# Generated by FakeRAM 2.0 (routing-friendly)
VERSION 5.7 ;
BUSBITCHARS "[]" ;
PROPERTYDEFINITIONS
  MACRO width INTEGER ;
  MACRO depth INTEGER ;
  MACRO banks INTEGER ;
END PROPERTYDEFINITIONS
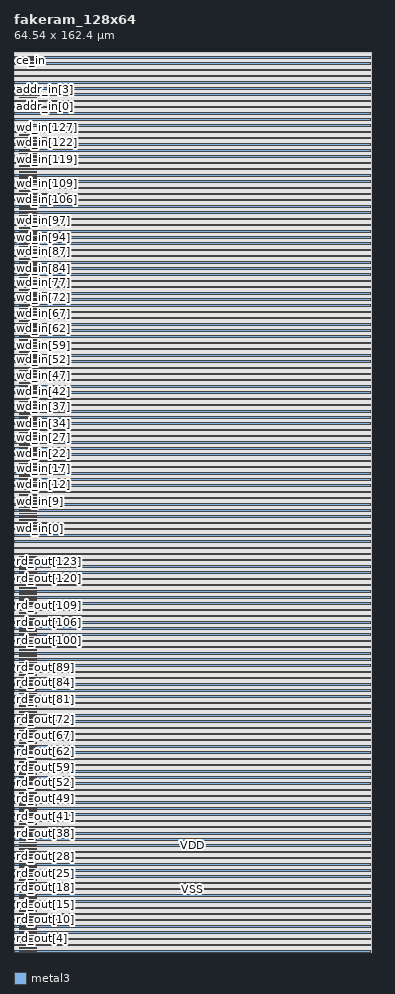
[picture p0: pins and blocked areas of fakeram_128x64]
MACRO fakeram_128x64
  PROPERTY width 128 ;
  PROPERTY depth 64 ;
  PROPERTY banks 1 ;
  FOREIGN fakeram_128x64 0 0 ;
  SYMMETRY X Y R90 ;
  SIZE 64.540 BY 162.400 ;
  CLASS BLOCK ;
  PIN rd_out[0]
    DIRECTION OUTPUT ;
    USE SIGNAL ;
    PORT
      LAYER metal3 ;
      RECT 1.000 0.140 3.000 0.210 ;
    END
    PORT
      LAYER metal3 ;
      RECT 1.000 0.105 4.000 0.245 ;
    END
  END rd_out[0]
  PIN rd_out[1]
    DIRECTION OUTPUT ;
    USE SIGNAL ;
    PORT
      LAYER metal3 ;
      RECT 1.000 0.700 3.000 0.770 ;
    END
    PORT
      LAYER metal3 ;
      RECT 1.000 0.665 4.000 0.805 ;
    END
  END rd_out[1]
  PIN rd_out[2]
    DIRECTION OUTPUT ;
    USE SIGNAL ;
    PORT
      LAYER metal3 ;
      RECT 1.000 1.260 3.000 1.330 ;
    END
    PORT
      LAYER metal3 ;
      RECT 1.000 1.225 4.000 1.365 ;
    END
  END rd_out[2]
  PIN rd_out[3]
    DIRECTION OUTPUT ;
    USE SIGNAL ;
    PORT
      LAYER metal3 ;
      RECT 1.000 1.820 3.000 1.890 ;
    END
    PORT
      LAYER metal3 ;
      RECT 1.000 1.785 4.000 1.925 ;
    END
  END rd_out[3]
  PIN rd_out[4]
    DIRECTION OUTPUT ;
    USE SIGNAL ;
    PORT
      LAYER metal3 ;
      RECT 1.000 2.380 3.000 2.450 ;
    END
    PORT
      LAYER metal3 ;
      RECT 1.000 2.345 4.000 2.485 ;
    END
  END rd_out[4]
  PIN rd_out[5]
    DIRECTION OUTPUT ;
    USE SIGNAL ;
    PORT
      LAYER metal3 ;
      RECT 1.000 2.940 3.000 3.010 ;
    END
    PORT
      LAYER metal3 ;
      RECT 1.000 2.905 4.000 3.045 ;
    END
  END rd_out[5]
  PIN rd_out[6]
    DIRECTION OUTPUT ;
    USE SIGNAL ;
    PORT
      LAYER metal3 ;
      RECT 1.000 3.500 3.000 3.570 ;
    END
    PORT
      LAYER metal3 ;
      RECT 1.000 3.465 4.000 3.605 ;
    END
  END rd_out[6]
  PIN rd_out[7]
    DIRECTION OUTPUT ;
    USE SIGNAL ;
    PORT
      LAYER metal3 ;
      RECT 1.000 4.060 3.000 4.130 ;
    END
    PORT
      LAYER metal3 ;
      RECT 1.000 4.025 4.000 4.165 ;
    END
  END rd_out[7]
  PIN rd_out[8]
    DIRECTION OUTPUT ;
    USE SIGNAL ;
    PORT
      LAYER metal3 ;
      RECT 1.000 4.620 3.000 4.690 ;
    END
    PORT
      LAYER metal3 ;
      RECT 1.000 4.585 4.000 4.725 ;
    END
  END rd_out[8]
  PIN rd_out[9]
    DIRECTION OUTPUT ;
    USE SIGNAL ;
    PORT
      LAYER metal3 ;
      RECT 1.000 5.180 3.000 5.250 ;
    END
    PORT
      LAYER metal3 ;
      RECT 1.000 5.145 4.000 5.285 ;
    END
  END rd_out[9]
  PIN rd_out[10]
    DIRECTION OUTPUT ;
    USE SIGNAL ;
    PORT
      LAYER metal3 ;
      RECT 1.000 5.740 3.000 5.810 ;
    END
    PORT
      LAYER metal3 ;
      RECT 1.000 5.705 4.000 5.845 ;
    END
  END rd_out[10]
  PIN rd_out[11]
    DIRECTION OUTPUT ;
    USE SIGNAL ;
    PORT
      LAYER metal3 ;
      RECT 1.000 6.300 3.000 6.370 ;
    END
    PORT
      LAYER metal3 ;
      RECT 1.000 6.265 4.000 6.405 ;
    END
  END rd_out[11]
  PIN rd_out[12]
    DIRECTION OUTPUT ;
    USE SIGNAL ;
    PORT
      LAYER metal3 ;
      RECT 1.000 6.860 3.000 6.930 ;
    END
    PORT
      LAYER metal3 ;
      RECT 1.000 6.825 4.000 6.965 ;
    END
  END rd_out[12]
  PIN rd_out[13]
    DIRECTION OUTPUT ;
    USE SIGNAL ;
    PORT
      LAYER metal3 ;
      RECT 1.000 7.420 3.000 7.490 ;
    END
    PORT
      LAYER metal3 ;
      RECT 1.000 7.385 4.000 7.525 ;
    END
  END rd_out[13]
  PIN rd_out[14]
    DIRECTION OUTPUT ;
    USE SIGNAL ;
    PORT
      LAYER metal3 ;
      RECT 1.000 7.980 3.000 8.050 ;
    END
    PORT
      LAYER metal3 ;
      RECT 1.000 7.945 4.000 8.085 ;
    END
  END rd_out[14]
  PIN rd_out[15]
    DIRECTION OUTPUT ;
    USE SIGNAL ;
    PORT
      LAYER metal3 ;
      RECT 1.000 8.540 3.000 8.610 ;
    END
    PORT
      LAYER metal3 ;
      RECT 1.000 8.505 4.000 8.645 ;
    END
  END rd_out[15]
  PIN rd_out[16]
    DIRECTION OUTPUT ;
    USE SIGNAL ;
    PORT
      LAYER metal3 ;
      RECT 1.000 9.100 3.000 9.170 ;
    END
    PORT
      LAYER metal3 ;
      RECT 1.000 9.065 4.000 9.205 ;
    END
  END rd_out[16]
  PIN rd_out[17]
    DIRECTION OUTPUT ;
    USE SIGNAL ;
    PORT
      LAYER metal3 ;
      RECT 1.000 9.660 3.000 9.730 ;
    END
    PORT
      LAYER metal3 ;
      RECT 1.000 9.625 4.000 9.765 ;
    END
  END rd_out[17]
  PIN rd_out[18]
    DIRECTION OUTPUT ;
    USE SIGNAL ;
    PORT
      LAYER metal3 ;
      RECT 1.000 10.220 3.000 10.290 ;
    END
    PORT
      LAYER metal3 ;
      RECT 1.000 10.185 4.000 10.325 ;
    END
  END rd_out[18]
  PIN rd_out[19]
    DIRECTION OUTPUT ;
    USE SIGNAL ;
    PORT
      LAYER metal3 ;
      RECT 1.000 10.780 3.000 10.850 ;
    END
    PORT
      LAYER metal3 ;
      RECT 1.000 10.745 4.000 10.885 ;
    END
  END rd_out[19]
  PIN rd_out[20]
    DIRECTION OUTPUT ;
    USE SIGNAL ;
    PORT
      LAYER metal3 ;
      RECT 1.000 11.340 3.000 11.410 ;
    END
    PORT
      LAYER metal3 ;
      RECT 1.000 11.305 4.000 11.445 ;
    END
  END rd_out[20]
  PIN rd_out[21]
    DIRECTION OUTPUT ;
    USE SIGNAL ;
    PORT
      LAYER metal3 ;
      RECT 1.000 11.900 3.000 11.970 ;
    END
    PORT
      LAYER metal3 ;
      RECT 1.000 11.865 4.000 12.005 ;
    END
  END rd_out[21]
  PIN rd_out[22]
    DIRECTION OUTPUT ;
    USE SIGNAL ;
    PORT
      LAYER metal3 ;
      RECT 1.000 12.460 3.000 12.530 ;
    END
    PORT
      LAYER metal3 ;
      RECT 1.000 12.425 4.000 12.565 ;
    END
  END rd_out[22]
  PIN rd_out[23]
    DIRECTION OUTPUT ;
    USE SIGNAL ;
    PORT
      LAYER metal3 ;
      RECT 1.000 13.020 3.000 13.090 ;
    END
    PORT
      LAYER metal3 ;
      RECT 1.000 12.985 4.000 13.125 ;
    END
  END rd_out[23]
  PIN rd_out[24]
    DIRECTION OUTPUT ;
    USE SIGNAL ;
    PORT
      LAYER metal3 ;
      RECT 1.000 13.580 3.000 13.650 ;
    END
    PORT
      LAYER metal3 ;
      RECT 1.000 13.545 4.000 13.685 ;
    END
  END rd_out[24]
  PIN rd_out[25]
    DIRECTION OUTPUT ;
    USE SIGNAL ;
    PORT
      LAYER metal3 ;
      RECT 1.000 14.140 3.000 14.210 ;
    END
    PORT
      LAYER metal3 ;
      RECT 1.000 14.105 4.000 14.245 ;
    END
  END rd_out[25]
  PIN rd_out[26]
    DIRECTION OUTPUT ;
    USE SIGNAL ;
    PORT
      LAYER metal3 ;
      RECT 1.000 14.700 3.000 14.770 ;
    END
    PORT
      LAYER metal3 ;
      RECT 1.000 14.665 4.000 14.805 ;
    END
  END rd_out[26]
  PIN rd_out[27]
    DIRECTION OUTPUT ;
    USE SIGNAL ;
    PORT
      LAYER metal3 ;
      RECT 1.000 15.260 3.000 15.330 ;
    END
    PORT
      LAYER metal3 ;
      RECT 1.000 15.225 4.000 15.365 ;
    END
  END rd_out[27]
  PIN rd_out[28]
    DIRECTION OUTPUT ;
    USE SIGNAL ;
    PORT
      LAYER metal3 ;
      RECT 1.000 15.820 3.000 15.890 ;
    END
    PORT
      LAYER metal3 ;
      RECT 1.000 15.785 4.000 15.925 ;
    END
  END rd_out[28]
  PIN rd_out[29]
    DIRECTION OUTPUT ;
    USE SIGNAL ;
    PORT
      LAYER metal3 ;
      RECT 1.000 16.380 3.000 16.450 ;
    END
    PORT
      LAYER metal3 ;
      RECT 1.000 16.345 4.000 16.485 ;
    END
  END rd_out[29]
  PIN rd_out[30]
    DIRECTION OUTPUT ;
    USE SIGNAL ;
    PORT
      LAYER metal3 ;
      RECT 1.000 16.940 3.000 17.010 ;
    END
    PORT
      LAYER metal3 ;
      RECT 1.000 16.905 4.000 17.045 ;
    END
  END rd_out[30]
  PIN rd_out[31]
    DIRECTION OUTPUT ;
    USE SIGNAL ;
    PORT
      LAYER metal3 ;
      RECT 1.000 17.500 3.000 17.570 ;
    END
    PORT
      LAYER metal3 ;
      RECT 1.000 17.465 4.000 17.605 ;
    END
  END rd_out[31]
  PIN rd_out[32]
    DIRECTION OUTPUT ;
    USE SIGNAL ;
    PORT
      LAYER metal3 ;
      RECT 1.000 18.060 3.000 18.130 ;
    END
    PORT
      LAYER metal3 ;
      RECT 1.000 18.025 4.000 18.165 ;
    END
  END rd_out[32]
  PIN rd_out[33]
    DIRECTION OUTPUT ;
    USE SIGNAL ;
    PORT
      LAYER metal3 ;
      RECT 1.000 18.620 3.000 18.690 ;
    END
    PORT
      LAYER metal3 ;
      RECT 1.000 18.585 4.000 18.725 ;
    END
  END rd_out[33]
  PIN rd_out[34]
    DIRECTION OUTPUT ;
    USE SIGNAL ;
    PORT
      LAYER metal3 ;
      RECT 1.000 19.180 3.000 19.250 ;
    END
    PORT
      LAYER metal3 ;
      RECT 1.000 19.145 4.000 19.285 ;
    END
  END rd_out[34]
  PIN rd_out[35]
    DIRECTION OUTPUT ;
    USE SIGNAL ;
    PORT
      LAYER metal3 ;
      RECT 1.000 19.740 3.000 19.810 ;
    END
    PORT
      LAYER metal3 ;
      RECT 1.000 19.705 4.000 19.845 ;
    END
  END rd_out[35]
  PIN rd_out[36]
    DIRECTION OUTPUT ;
    USE SIGNAL ;
    PORT
      LAYER metal3 ;
      RECT 1.000 20.300 3.000 20.370 ;
    END
    PORT
      LAYER metal3 ;
      RECT 1.000 20.265 4.000 20.405 ;
    END
  END rd_out[36]
  PIN rd_out[37]
    DIRECTION OUTPUT ;
    USE SIGNAL ;
    PORT
      LAYER metal3 ;
      RECT 1.000 20.860 3.000 20.930 ;
    END
    PORT
      LAYER metal3 ;
      RECT 1.000 20.825 4.000 20.965 ;
    END
  END rd_out[37]
  PIN rd_out[38]
    DIRECTION OUTPUT ;
    USE SIGNAL ;
    PORT
      LAYER metal3 ;
      RECT 1.000 21.420 3.000 21.490 ;
    END
    PORT
      LAYER metal3 ;
      RECT 1.000 21.385 4.000 21.525 ;
    END
  END rd_out[38]
  PIN rd_out[39]
    DIRECTION OUTPUT ;
    USE SIGNAL ;
    PORT
      LAYER metal3 ;
      RECT 1.000 21.980 3.000 22.050 ;
    END
    PORT
      LAYER metal3 ;
      RECT 1.000 21.945 4.000 22.085 ;
    END
  END rd_out[39]
  PIN rd_out[40]
    DIRECTION OUTPUT ;
    USE SIGNAL ;
    PORT
      LAYER metal3 ;
      RECT 1.000 22.540 3.000 22.610 ;
    END
    PORT
      LAYER metal3 ;
      RECT 1.000 22.505 4.000 22.645 ;
    END
  END rd_out[40]
  PIN rd_out[41]
    DIRECTION OUTPUT ;
    USE SIGNAL ;
    PORT
      LAYER metal3 ;
      RECT 1.000 23.100 3.000 23.170 ;
    END
    PORT
      LAYER metal3 ;
      RECT 1.000 23.065 4.000 23.205 ;
    END
  END rd_out[41]
  PIN rd_out[42]
    DIRECTION OUTPUT ;
    USE SIGNAL ;
    PORT
      LAYER metal3 ;
      RECT 1.000 23.660 3.000 23.730 ;
    END
    PORT
      LAYER metal3 ;
      RECT 1.000 23.625 4.000 23.765 ;
    END
  END rd_out[42]
  PIN rd_out[43]
    DIRECTION OUTPUT ;
    USE SIGNAL ;
    PORT
      LAYER metal3 ;
      RECT 1.000 24.220 3.000 24.290 ;
    END
    PORT
      LAYER metal3 ;
      RECT 1.000 24.185 4.000 24.325 ;
    END
  END rd_out[43]
  PIN rd_out[44]
    DIRECTION OUTPUT ;
    USE SIGNAL ;
    PORT
      LAYER metal3 ;
      RECT 1.000 24.780 3.000 24.850 ;
    END
    PORT
      LAYER metal3 ;
      RECT 1.000 24.745 4.000 24.885 ;
    END
  END rd_out[44]
  PIN rd_out[45]
    DIRECTION OUTPUT ;
    USE SIGNAL ;
    PORT
      LAYER metal3 ;
      RECT 1.000 25.340 3.000 25.410 ;
    END
    PORT
      LAYER metal3 ;
      RECT 1.000 25.305 4.000 25.445 ;
    END
  END rd_out[45]
  PIN rd_out[46]
    DIRECTION OUTPUT ;
    USE SIGNAL ;
    PORT
      LAYER metal3 ;
      RECT 1.000 25.900 3.000 25.970 ;
    END
    PORT
      LAYER metal3 ;
      RECT 1.000 25.865 4.000 26.005 ;
    END
  END rd_out[46]
  PIN rd_out[47]
    DIRECTION OUTPUT ;
    USE SIGNAL ;
    PORT
      LAYER metal3 ;
      RECT 1.000 26.460 3.000 26.530 ;
    END
    PORT
      LAYER metal3 ;
      RECT 1.000 26.425 4.000 26.565 ;
    END
  END rd_out[47]
  PIN rd_out[48]
    DIRECTION OUTPUT ;
    USE SIGNAL ;
    PORT
      LAYER metal3 ;
      RECT 1.000 27.020 3.000 27.090 ;
    END
    PORT
      LAYER metal3 ;
      RECT 1.000 26.985 4.000 27.125 ;
    END
  END rd_out[48]
  PIN rd_out[49]
    DIRECTION OUTPUT ;
    USE SIGNAL ;
    PORT
      LAYER metal3 ;
      RECT 1.000 27.580 3.000 27.650 ;
    END
    PORT
      LAYER metal3 ;
      RECT 1.000 27.545 4.000 27.685 ;
    END
  END rd_out[49]
  PIN rd_out[50]
    DIRECTION OUTPUT ;
    USE SIGNAL ;
    PORT
      LAYER metal3 ;
      RECT 1.000 28.140 3.000 28.210 ;
    END
    PORT
      LAYER metal3 ;
      RECT 1.000 28.105 4.000 28.245 ;
    END
  END rd_out[50]
  PIN rd_out[51]
    DIRECTION OUTPUT ;
    USE SIGNAL ;
    PORT
      LAYER metal3 ;
      RECT 1.000 28.700 3.000 28.770 ;
    END
    PORT
      LAYER metal3 ;
      RECT 1.000 28.665 4.000 28.805 ;
    END
  END rd_out[51]
  PIN rd_out[52]
    DIRECTION OUTPUT ;
    USE SIGNAL ;
    PORT
      LAYER metal3 ;
      RECT 1.000 29.260 3.000 29.330 ;
    END
    PORT
      LAYER metal3 ;
      RECT 1.000 29.225 4.000 29.365 ;
    END
  END rd_out[52]
  PIN rd_out[53]
    DIRECTION OUTPUT ;
    USE SIGNAL ;
    PORT
      LAYER metal3 ;
      RECT 1.000 29.820 3.000 29.890 ;
    END
    PORT
      LAYER metal3 ;
      RECT 1.000 29.785 4.000 29.925 ;
    END
  END rd_out[53]
  PIN rd_out[54]
    DIRECTION OUTPUT ;
    USE SIGNAL ;
    PORT
      LAYER metal3 ;
      RECT 1.000 30.380 3.000 30.450 ;
    END
    PORT
      LAYER metal3 ;
      RECT 1.000 30.345 4.000 30.485 ;
    END
  END rd_out[54]
  PIN rd_out[55]
    DIRECTION OUTPUT ;
    USE SIGNAL ;
    PORT
      LAYER metal3 ;
      RECT 1.000 30.940 3.000 31.010 ;
    END
    PORT
      LAYER metal3 ;
      RECT 1.000 30.905 4.000 31.045 ;
    END
  END rd_out[55]
  PIN rd_out[56]
    DIRECTION OUTPUT ;
    USE SIGNAL ;
    PORT
      LAYER metal3 ;
      RECT 1.000 31.500 3.000 31.570 ;
    END
    PORT
      LAYER metal3 ;
      RECT 1.000 31.465 4.000 31.605 ;
    END
  END rd_out[56]
  PIN rd_out[57]
    DIRECTION OUTPUT ;
    USE SIGNAL ;
    PORT
      LAYER metal3 ;
      RECT 1.000 32.060 3.000 32.130 ;
    END
    PORT
      LAYER metal3 ;
      RECT 1.000 32.025 4.000 32.165 ;
    END
  END rd_out[57]
  PIN rd_out[58]
    DIRECTION OUTPUT ;
    USE SIGNAL ;
    PORT
      LAYER metal3 ;
      RECT 1.000 32.620 3.000 32.690 ;
    END
    PORT
      LAYER metal3 ;
      RECT 1.000 32.585 4.000 32.725 ;
    END
  END rd_out[58]
  PIN rd_out[59]
    DIRECTION OUTPUT ;
    USE SIGNAL ;
    PORT
      LAYER metal3 ;
      RECT 1.000 33.180 3.000 33.250 ;
    END
    PORT
      LAYER metal3 ;
      RECT 1.000 33.145 4.000 33.285 ;
    END
  END rd_out[59]
  PIN rd_out[60]
    DIRECTION OUTPUT ;
    USE SIGNAL ;
    PORT
      LAYER metal3 ;
      RECT 1.000 33.740 3.000 33.810 ;
    END
    PORT
      LAYER metal3 ;
      RECT 1.000 33.705 4.000 33.845 ;
    END
  END rd_out[60]
  PIN rd_out[61]
    DIRECTION OUTPUT ;
    USE SIGNAL ;
    PORT
      LAYER metal3 ;
      RECT 1.000 34.300 3.000 34.370 ;
    END
    PORT
      LAYER metal3 ;
      RECT 1.000 34.265 4.000 34.405 ;
    END
  END rd_out[61]
  PIN rd_out[62]
    DIRECTION OUTPUT ;
    USE SIGNAL ;
    PORT
      LAYER metal3 ;
      RECT 1.000 34.860 3.000 34.930 ;
    END
    PORT
      LAYER metal3 ;
      RECT 1.000 34.825 4.000 34.965 ;
    END
  END rd_out[62]
  PIN rd_out[63]
    DIRECTION OUTPUT ;
    USE SIGNAL ;
    PORT
      LAYER metal3 ;
      RECT 1.000 35.420 3.000 35.490 ;
    END
    PORT
      LAYER metal3 ;
      RECT 1.000 35.385 4.000 35.525 ;
    END
  END rd_out[63]
  PIN rd_out[64]
    DIRECTION OUTPUT ;
    USE SIGNAL ;
    PORT
      LAYER metal3 ;
      RECT 1.000 35.980 3.000 36.050 ;
    END
    PORT
      LAYER metal3 ;
      RECT 1.000 35.945 4.000 36.085 ;
    END
  END rd_out[64]
  PIN rd_out[65]
    DIRECTION OUTPUT ;
    USE SIGNAL ;
    PORT
      LAYER metal3 ;
      RECT 1.000 36.540 3.000 36.610 ;
    END
    PORT
      LAYER metal3 ;
      RECT 1.000 36.505 4.000 36.645 ;
    END
  END rd_out[65]
  PIN rd_out[66]
    DIRECTION OUTPUT ;
    USE SIGNAL ;
    PORT
      LAYER metal3 ;
      RECT 1.000 37.100 3.000 37.170 ;
    END
    PORT
      LAYER metal3 ;
      RECT 1.000 37.065 4.000 37.205 ;
    END
  END rd_out[66]
  PIN rd_out[67]
    DIRECTION OUTPUT ;
    USE SIGNAL ;
    PORT
      LAYER metal3 ;
      RECT 1.000 37.660 3.000 37.730 ;
    END
    PORT
      LAYER metal3 ;
      RECT 1.000 37.625 4.000 37.765 ;
    END
  END rd_out[67]
  PIN rd_out[68]
    DIRECTION OUTPUT ;
    USE SIGNAL ;
    PORT
      LAYER metal3 ;
      RECT 1.000 38.220 3.000 38.290 ;
    END
    PORT
      LAYER metal3 ;
      RECT 1.000 38.185 4.000 38.325 ;
    END
  END rd_out[68]
  PIN rd_out[69]
    DIRECTION OUTPUT ;
    USE SIGNAL ;
    PORT
      LAYER metal3 ;
      RECT 1.000 38.780 3.000 38.850 ;
    END
    PORT
      LAYER metal3 ;
      RECT 1.000 38.745 4.000 38.885 ;
    END
  END rd_out[69]
  PIN rd_out[70]
    DIRECTION OUTPUT ;
    USE SIGNAL ;
    PORT
      LAYER metal3 ;
      RECT 1.000 39.340 3.000 39.410 ;
    END
    PORT
      LAYER metal3 ;
      RECT 1.000 39.305 4.000 39.445 ;
    END
  END rd_out[70]
  PIN rd_out[71]
    DIRECTION OUTPUT ;
    USE SIGNAL ;
    PORT
      LAYER metal3 ;
      RECT 1.000 39.900 3.000 39.970 ;
    END
    PORT
      LAYER metal3 ;
      RECT 1.000 39.865 4.000 40.005 ;
    END
  END rd_out[71]
  PIN rd_out[72]
    DIRECTION OUTPUT ;
    USE SIGNAL ;
    PORT
      LAYER metal3 ;
      RECT 1.000 40.460 3.000 40.530 ;
    END
    PORT
      LAYER metal3 ;
      RECT 1.000 40.425 4.000 40.565 ;
    END
  END rd_out[72]
  PIN rd_out[73]
    DIRECTION OUTPUT ;
    USE SIGNAL ;
    PORT
      LAYER metal3 ;
      RECT 1.000 41.020 3.000 41.090 ;
    END
    PORT
      LAYER metal3 ;
      RECT 1.000 40.985 4.000 41.125 ;
    END
  END rd_out[73]
  PIN rd_out[74]
    DIRECTION OUTPUT ;
    USE SIGNAL ;
    PORT
      LAYER metal3 ;
      RECT 1.000 41.580 3.000 41.650 ;
    END
    PORT
      LAYER metal3 ;
      RECT 1.000 41.545 4.000 41.685 ;
    END
  END rd_out[74]
  PIN rd_out[75]
    DIRECTION OUTPUT ;
    USE SIGNAL ;
    PORT
      LAYER metal3 ;
      RECT 1.000 42.140 3.000 42.210 ;
    END
    PORT
      LAYER metal3 ;
      RECT 1.000 42.105 4.000 42.245 ;
    END
  END rd_out[75]
  PIN rd_out[76]
    DIRECTION OUTPUT ;
    USE SIGNAL ;
    PORT
      LAYER metal3 ;
      RECT 1.000 42.700 3.000 42.770 ;
    END
    PORT
      LAYER metal3 ;
      RECT 1.000 42.665 4.000 42.805 ;
    END
  END rd_out[76]
  PIN rd_out[77]
    DIRECTION OUTPUT ;
    USE SIGNAL ;
    PORT
      LAYER metal3 ;
      RECT 1.000 43.260 3.000 43.330 ;
    END
    PORT
      LAYER metal3 ;
      RECT 1.000 43.225 4.000 43.365 ;
    END
  END rd_out[77]
  PIN rd_out[78]
    DIRECTION OUTPUT ;
    USE SIGNAL ;
    PORT
      LAYER metal3 ;
      RECT 1.000 43.820 3.000 43.890 ;
    END
    PORT
      LAYER metal3 ;
      RECT 1.000 43.785 4.000 43.925 ;
    END
  END rd_out[78]
  PIN rd_out[79]
    DIRECTION OUTPUT ;
    USE SIGNAL ;
    PORT
      LAYER metal3 ;
      RECT 1.000 44.380 3.000 44.450 ;
    END
    PORT
      LAYER metal3 ;
      RECT 1.000 44.345 4.000 44.485 ;
    END
  END rd_out[79]
  PIN rd_out[80]
    DIRECTION OUTPUT ;
    USE SIGNAL ;
    PORT
      LAYER metal3 ;
      RECT 1.000 44.940 3.000 45.010 ;
    END
    PORT
      LAYER metal3 ;
      RECT 1.000 44.905 4.000 45.045 ;
    END
  END rd_out[80]
  PIN rd_out[81]
    DIRECTION OUTPUT ;
    USE SIGNAL ;
    PORT
      LAYER metal3 ;
      RECT 1.000 45.500 3.000 45.570 ;
    END
    PORT
      LAYER metal3 ;
      RECT 1.000 45.465 4.000 45.605 ;
    END
  END rd_out[81]
  PIN rd_out[82]
    DIRECTION OUTPUT ;
    USE SIGNAL ;
    PORT
      LAYER metal3 ;
      RECT 1.000 46.060 3.000 46.130 ;
    END
    PORT
      LAYER metal3 ;
      RECT 1.000 46.025 4.000 46.165 ;
    END
  END rd_out[82]
  PIN rd_out[83]
    DIRECTION OUTPUT ;
    USE SIGNAL ;
    PORT
      LAYER metal3 ;
      RECT 1.000 46.620 3.000 46.690 ;
    END
    PORT
      LAYER metal3 ;
      RECT 1.000 46.585 4.000 46.725 ;
    END
  END rd_out[83]
  PIN rd_out[84]
    DIRECTION OUTPUT ;
    USE SIGNAL ;
    PORT
      LAYER metal3 ;
      RECT 1.000 47.180 3.000 47.250 ;
    END
    PORT
      LAYER metal3 ;
      RECT 1.000 47.145 4.000 47.285 ;
    END
  END rd_out[84]
  PIN rd_out[85]
    DIRECTION OUTPUT ;
    USE SIGNAL ;
    PORT
      LAYER metal3 ;
      RECT 1.000 47.740 3.000 47.810 ;
    END
    PORT
      LAYER metal3 ;
      RECT 1.000 47.705 4.000 47.845 ;
    END
  END rd_out[85]
  PIN rd_out[86]
    DIRECTION OUTPUT ;
    USE SIGNAL ;
    PORT
      LAYER metal3 ;
      RECT 1.000 48.300 3.000 48.370 ;
    END
    PORT
      LAYER metal3 ;
      RECT 1.000 48.265 4.000 48.405 ;
    END
  END rd_out[86]
  PIN rd_out[87]
    DIRECTION OUTPUT ;
    USE SIGNAL ;
    PORT
      LAYER metal3 ;
      RECT 1.000 48.860 3.000 48.930 ;
    END
    PORT
      LAYER metal3 ;
      RECT 1.000 48.825 4.000 48.965 ;
    END
  END rd_out[87]
  PIN rd_out[88]
    DIRECTION OUTPUT ;
    USE SIGNAL ;
    PORT
      LAYER metal3 ;
      RECT 1.000 49.420 3.000 49.490 ;
    END
    PORT
      LAYER metal3 ;
      RECT 1.000 49.385 4.000 49.525 ;
    END
  END rd_out[88]
  PIN rd_out[89]
    DIRECTION OUTPUT ;
    USE SIGNAL ;
    PORT
      LAYER metal3 ;
      RECT 1.000 49.980 3.000 50.050 ;
    END
    PORT
      LAYER metal3 ;
      RECT 1.000 49.945 4.000 50.085 ;
    END
  END rd_out[89]
  PIN rd_out[90]
    DIRECTION OUTPUT ;
    USE SIGNAL ;
    PORT
      LAYER metal3 ;
      RECT 1.000 50.540 3.000 50.610 ;
    END
    PORT
      LAYER metal3 ;
      RECT 1.000 50.505 4.000 50.645 ;
    END
  END rd_out[90]
  PIN rd_out[91]
    DIRECTION OUTPUT ;
    USE SIGNAL ;
    PORT
      LAYER metal3 ;
      RECT 1.000 51.100 3.000 51.170 ;
    END
    PORT
      LAYER metal3 ;
      RECT 1.000 51.065 4.000 51.205 ;
    END
  END rd_out[91]
  PIN rd_out[92]
    DIRECTION OUTPUT ;
    USE SIGNAL ;
    PORT
      LAYER metal3 ;
      RECT 1.000 51.660 3.000 51.730 ;
    END
    PORT
      LAYER metal3 ;
      RECT 1.000 51.625 4.000 51.765 ;
    END
  END rd_out[92]
  PIN rd_out[93]
    DIRECTION OUTPUT ;
    USE SIGNAL ;
    PORT
      LAYER metal3 ;
      RECT 1.000 52.220 3.000 52.290 ;
    END
    PORT
      LAYER metal3 ;
      RECT 1.000 52.185 4.000 52.325 ;
    END
  END rd_out[93]
  PIN rd_out[94]
    DIRECTION OUTPUT ;
    USE SIGNAL ;
    PORT
      LAYER metal3 ;
      RECT 1.000 52.780 3.000 52.850 ;
    END
    PORT
      LAYER metal3 ;
      RECT 1.000 52.745 4.000 52.885 ;
    END
  END rd_out[94]
  PIN rd_out[95]
    DIRECTION OUTPUT ;
    USE SIGNAL ;
    PORT
      LAYER metal3 ;
      RECT 1.000 53.340 3.000 53.410 ;
    END
    PORT
      LAYER metal3 ;
      RECT 1.000 53.305 4.000 53.445 ;
    END
  END rd_out[95]
  PIN rd_out[96]
    DIRECTION OUTPUT ;
    USE SIGNAL ;
    PORT
      LAYER metal3 ;
      RECT 1.000 53.900 3.000 53.970 ;
    END
    PORT
      LAYER metal3 ;
      RECT 1.000 53.865 4.000 54.005 ;
    END
  END rd_out[96]
  PIN rd_out[97]
    DIRECTION OUTPUT ;
    USE SIGNAL ;
    PORT
      LAYER metal3 ;
      RECT 1.000 54.460 3.000 54.530 ;
    END
    PORT
      LAYER metal3 ;
      RECT 1.000 54.425 4.000 54.565 ;
    END
  END rd_out[97]
  PIN rd_out[98]
    DIRECTION OUTPUT ;
    USE SIGNAL ;
    PORT
      LAYER metal3 ;
      RECT 1.000 55.020 3.000 55.090 ;
    END
    PORT
      LAYER metal3 ;
      RECT 1.000 54.985 4.000 55.125 ;
    END
  END rd_out[98]
  PIN rd_out[99]
    DIRECTION OUTPUT ;
    USE SIGNAL ;
    PORT
      LAYER metal3 ;
      RECT 1.000 55.580 3.000 55.650 ;
    END
    PORT
      LAYER metal3 ;
      RECT 1.000 55.545 4.000 55.685 ;
    END
  END rd_out[99]
  PIN rd_out[100]
    DIRECTION OUTPUT ;
    USE SIGNAL ;
    PORT
      LAYER metal3 ;
      RECT 1.000 56.140 3.000 56.210 ;
    END
    PORT
      LAYER metal3 ;
      RECT 1.000 56.105 4.000 56.245 ;
    END
  END rd_out[100]
  PIN rd_out[101]
    DIRECTION OUTPUT ;
    USE SIGNAL ;
    PORT
      LAYER metal3 ;
      RECT 1.000 56.700 3.000 56.770 ;
    END
    PORT
      LAYER metal3 ;
      RECT 1.000 56.665 4.000 56.805 ;
    END
  END rd_out[101]
  PIN rd_out[102]
    DIRECTION OUTPUT ;
    USE SIGNAL ;
    PORT
      LAYER metal3 ;
      RECT 1.000 57.260 3.000 57.330 ;
    END
    PORT
      LAYER metal3 ;
      RECT 1.000 57.225 4.000 57.365 ;
    END
  END rd_out[102]
  PIN rd_out[103]
    DIRECTION OUTPUT ;
    USE SIGNAL ;
    PORT
      LAYER metal3 ;
      RECT 1.000 57.820 3.000 57.890 ;
    END
    PORT
      LAYER metal3 ;
      RECT 1.000 57.785 4.000 57.925 ;
    END
  END rd_out[103]
  PIN rd_out[104]
    DIRECTION OUTPUT ;
    USE SIGNAL ;
    PORT
      LAYER metal3 ;
      RECT 1.000 58.380 3.000 58.450 ;
    END
    PORT
      LAYER metal3 ;
      RECT 1.000 58.345 4.000 58.485 ;
    END
  END rd_out[104]
  PIN rd_out[105]
    DIRECTION OUTPUT ;
    USE SIGNAL ;
    PORT
      LAYER metal3 ;
      RECT 1.000 58.940 3.000 59.010 ;
    END
    PORT
      LAYER metal3 ;
      RECT 1.000 58.905 4.000 59.045 ;
    END
  END rd_out[105]
  PIN rd_out[106]
    DIRECTION OUTPUT ;
    USE SIGNAL ;
    PORT
      LAYER metal3 ;
      RECT 1.000 59.500 3.000 59.570 ;
    END
    PORT
      LAYER metal3 ;
      RECT 1.000 59.465 4.000 59.605 ;
    END
  END rd_out[106]
  PIN rd_out[107]
    DIRECTION OUTPUT ;
    USE SIGNAL ;
    PORT
      LAYER metal3 ;
      RECT 1.000 60.060 3.000 60.130 ;
    END
    PORT
      LAYER metal3 ;
      RECT 1.000 60.025 4.000 60.165 ;
    END
  END rd_out[107]
  PIN rd_out[108]
    DIRECTION OUTPUT ;
    USE SIGNAL ;
    PORT
      LAYER metal3 ;
      RECT 1.000 60.620 3.000 60.690 ;
    END
    PORT
      LAYER metal3 ;
      RECT 1.000 60.585 4.000 60.725 ;
    END
  END rd_out[108]
  PIN rd_out[109]
    DIRECTION OUTPUT ;
    USE SIGNAL ;
    PORT
      LAYER metal3 ;
      RECT 1.000 61.180 3.000 61.250 ;
    END
    PORT
      LAYER metal3 ;
      RECT 1.000 61.145 4.000 61.285 ;
    END
  END rd_out[109]
  PIN rd_out[110]
    DIRECTION OUTPUT ;
    USE SIGNAL ;
    PORT
      LAYER metal3 ;
      RECT 1.000 61.740 3.000 61.810 ;
    END
    PORT
      LAYER metal3 ;
      RECT 1.000 61.705 4.000 61.845 ;
    END
  END rd_out[110]
  PIN rd_out[111]
    DIRECTION OUTPUT ;
    USE SIGNAL ;
    PORT
      LAYER metal3 ;
      RECT 1.000 62.300 3.000 62.370 ;
    END
    PORT
      LAYER metal3 ;
      RECT 1.000 62.265 4.000 62.405 ;
    END
  END rd_out[111]
  PIN rd_out[112]
    DIRECTION OUTPUT ;
    USE SIGNAL ;
    PORT
      LAYER metal3 ;
      RECT 1.000 62.860 3.000 62.930 ;
    END
    PORT
      LAYER metal3 ;
      RECT 1.000 62.825 4.000 62.965 ;
    END
  END rd_out[112]
  PIN rd_out[113]
    DIRECTION OUTPUT ;
    USE SIGNAL ;
    PORT
      LAYER metal3 ;
      RECT 1.000 63.420 3.000 63.490 ;
    END
    PORT
      LAYER metal3 ;
      RECT 1.000 63.385 4.000 63.525 ;
    END
  END rd_out[113]
  PIN rd_out[114]
    DIRECTION OUTPUT ;
    USE SIGNAL ;
    PORT
      LAYER metal3 ;
      RECT 1.000 63.980 3.000 64.050 ;
    END
    PORT
      LAYER metal3 ;
      RECT 1.000 63.945 4.000 64.085 ;
    END
  END rd_out[114]
  PIN rd_out[115]
    DIRECTION OUTPUT ;
    USE SIGNAL ;
    PORT
      LAYER metal3 ;
      RECT 1.000 64.540 3.000 64.610 ;
    END
    PORT
      LAYER metal3 ;
      RECT 1.000 64.505 4.000 64.645 ;
    END
  END rd_out[115]
  PIN rd_out[116]
    DIRECTION OUTPUT ;
    USE SIGNAL ;
    PORT
      LAYER metal3 ;
      RECT 1.000 65.100 3.000 65.170 ;
    END
    PORT
      LAYER metal3 ;
      RECT 1.000 65.065 4.000 65.205 ;
    END
  END rd_out[116]
  PIN rd_out[117]
    DIRECTION OUTPUT ;
    USE SIGNAL ;
    PORT
      LAYER metal3 ;
      RECT 1.000 65.660 3.000 65.730 ;
    END
    PORT
      LAYER metal3 ;
      RECT 1.000 65.625 4.000 65.765 ;
    END
  END rd_out[117]
  PIN rd_out[118]
    DIRECTION OUTPUT ;
    USE SIGNAL ;
    PORT
      LAYER metal3 ;
      RECT 1.000 66.220 3.000 66.290 ;
    END
    PORT
      LAYER metal3 ;
      RECT 1.000 66.185 4.000 66.325 ;
    END
  END rd_out[118]
  PIN rd_out[119]
    DIRECTION OUTPUT ;
    USE SIGNAL ;
    PORT
      LAYER metal3 ;
      RECT 1.000 66.780 3.000 66.850 ;
    END
    PORT
      LAYER metal3 ;
      RECT 1.000 66.745 4.000 66.885 ;
    END
  END rd_out[119]
  PIN rd_out[120]
    DIRECTION OUTPUT ;
    USE SIGNAL ;
    PORT
      LAYER metal3 ;
      RECT 1.000 67.340 3.000 67.410 ;
    END
    PORT
      LAYER metal3 ;
      RECT 1.000 67.305 4.000 67.445 ;
    END
  END rd_out[120]
  PIN rd_out[121]
    DIRECTION OUTPUT ;
    USE SIGNAL ;
    PORT
      LAYER metal3 ;
      RECT 1.000 67.900 3.000 67.970 ;
    END
    PORT
      LAYER metal3 ;
      RECT 1.000 67.865 4.000 68.005 ;
    END
  END rd_out[121]
  PIN rd_out[122]
    DIRECTION OUTPUT ;
    USE SIGNAL ;
    PORT
      LAYER metal3 ;
      RECT 1.000 68.460 3.000 68.530 ;
    END
    PORT
      LAYER metal3 ;
      RECT 1.000 68.425 4.000 68.565 ;
    END
  END rd_out[122]
  PIN rd_out[123]
    DIRECTION OUTPUT ;
    USE SIGNAL ;
    PORT
      LAYER metal3 ;
      RECT 1.000 69.020 3.000 69.090 ;
    END
    PORT
      LAYER metal3 ;
      RECT 1.000 68.985 4.000 69.125 ;
    END
  END rd_out[123]
  PIN rd_out[124]
    DIRECTION OUTPUT ;
    USE SIGNAL ;
    PORT
      LAYER metal3 ;
      RECT 1.000 69.580 3.000 69.650 ;
    END
    PORT
      LAYER metal3 ;
      RECT 1.000 69.545 4.000 69.685 ;
    END
  END rd_out[124]
  PIN rd_out[125]
    DIRECTION OUTPUT ;
    USE SIGNAL ;
    PORT
      LAYER metal3 ;
      RECT 1.000 70.140 3.000 70.210 ;
    END
    PORT
      LAYER metal3 ;
      RECT 1.000 70.105 4.000 70.245 ;
    END
  END rd_out[125]
  PIN rd_out[126]
    DIRECTION OUTPUT ;
    USE SIGNAL ;
    PORT
      LAYER metal3 ;
      RECT 1.000 70.700 3.000 70.770 ;
    END
    PORT
      LAYER metal3 ;
      RECT 1.000 70.665 4.000 70.805 ;
    END
  END rd_out[126]
  PIN rd_out[127]
    DIRECTION OUTPUT ;
    USE SIGNAL ;
    PORT
      LAYER metal3 ;
      RECT 1.000 71.260 3.000 71.330 ;
    END
    PORT
      LAYER metal3 ;
      RECT 1.000 71.225 4.000 71.365 ;
    END
  END rd_out[127]
  PIN wd_in[0]
    DIRECTION INPUT ;
    USE SIGNAL ;
    PORT
      LAYER metal3 ;
      RECT 1.000 76.300 3.000 76.370 ;
    END
    PORT
      LAYER metal3 ;
      RECT 1.000 76.265 4.000 76.405 ;
    END
  END wd_in[0]
  PIN wd_in[1]
    DIRECTION INPUT ;
    USE SIGNAL ;
    PORT
      LAYER metal3 ;
      RECT 1.000 76.860 3.000 76.930 ;
    END
    PORT
      LAYER metal3 ;
      RECT 1.000 76.825 4.000 76.965 ;
    END
  END wd_in[1]
  PIN wd_in[2]
    DIRECTION INPUT ;
    USE SIGNAL ;
    PORT
      LAYER metal3 ;
      RECT 1.000 77.420 3.000 77.490 ;
    END
    PORT
      LAYER metal3 ;
      RECT 1.000 77.385 4.000 77.525 ;
    END
  END wd_in[2]
  PIN wd_in[3]
    DIRECTION INPUT ;
    USE SIGNAL ;
    PORT
      LAYER metal3 ;
      RECT 1.000 77.980 3.000 78.050 ;
    END
    PORT
      LAYER metal3 ;
      RECT 1.000 77.945 4.000 78.085 ;
    END
  END wd_in[3]
  PIN wd_in[4]
    DIRECTION INPUT ;
    USE SIGNAL ;
    PORT
      LAYER metal3 ;
      RECT 1.000 78.540 3.000 78.610 ;
    END
    PORT
      LAYER metal3 ;
      RECT 1.000 78.505 4.000 78.645 ;
    END
  END wd_in[4]
  PIN wd_in[5]
    DIRECTION INPUT ;
    USE SIGNAL ;
    PORT
      LAYER metal3 ;
      RECT 1.000 79.100 3.000 79.170 ;
    END
    PORT
      LAYER metal3 ;
      RECT 1.000 79.065 4.000 79.205 ;
    END
  END wd_in[5]
  PIN wd_in[6]
    DIRECTION INPUT ;
    USE SIGNAL ;
    PORT
      LAYER metal3 ;
      RECT 1.000 79.660 3.000 79.730 ;
    END
    PORT
      LAYER metal3 ;
      RECT 1.000 79.625 4.000 79.765 ;
    END
  END wd_in[6]
  PIN wd_in[7]
    DIRECTION INPUT ;
    USE SIGNAL ;
    PORT
      LAYER metal3 ;
      RECT 1.000 80.220 3.000 80.290 ;
    END
    PORT
      LAYER metal3 ;
      RECT 1.000 80.185 4.000 80.325 ;
    END
  END wd_in[7]
  PIN wd_in[8]
    DIRECTION INPUT ;
    USE SIGNAL ;
    PORT
      LAYER metal3 ;
      RECT 1.000 80.780 3.000 80.850 ;
    END
    PORT
      LAYER metal3 ;
      RECT 1.000 80.745 4.000 80.885 ;
    END
  END wd_in[8]
  PIN wd_in[9]
    DIRECTION INPUT ;
    USE SIGNAL ;
    PORT
      LAYER metal3 ;
      RECT 1.000 81.340 3.000 81.410 ;
    END
    PORT
      LAYER metal3 ;
      RECT 1.000 81.305 4.000 81.445 ;
    END
  END wd_in[9]
  PIN wd_in[10]
    DIRECTION INPUT ;
    USE SIGNAL ;
    PORT
      LAYER metal3 ;
      RECT 1.000 81.900 3.000 81.970 ;
    END
    PORT
      LAYER metal3 ;
      RECT 1.000 81.865 4.000 82.005 ;
    END
  END wd_in[10]
  PIN wd_in[11]
    DIRECTION INPUT ;
    USE SIGNAL ;
    PORT
      LAYER metal3 ;
      RECT 1.000 82.460 3.000 82.530 ;
    END
    PORT
      LAYER metal3 ;
      RECT 1.000 82.425 4.000 82.565 ;
    END
  END wd_in[11]
  PIN wd_in[12]
    DIRECTION INPUT ;
    USE SIGNAL ;
    PORT
      LAYER metal3 ;
      RECT 1.000 83.020 3.000 83.090 ;
    END
    PORT
      LAYER metal3 ;
      RECT 1.000 82.985 4.000 83.125 ;
    END
  END wd_in[12]
  PIN wd_in[13]
    DIRECTION INPUT ;
    USE SIGNAL ;
    PORT
      LAYER metal3 ;
      RECT 1.000 83.580 3.000 83.650 ;
    END
    PORT
      LAYER metal3 ;
      RECT 1.000 83.545 4.000 83.685 ;
    END
  END wd_in[13]
  PIN wd_in[14]
    DIRECTION INPUT ;
    USE SIGNAL ;
    PORT
      LAYER metal3 ;
      RECT 1.000 84.140 3.000 84.210 ;
    END
    PORT
      LAYER metal3 ;
      RECT 1.000 84.105 4.000 84.245 ;
    END
  END wd_in[14]
  PIN wd_in[15]
    DIRECTION INPUT ;
    USE SIGNAL ;
    PORT
      LAYER metal3 ;
      RECT 1.000 84.700 3.000 84.770 ;
    END
    PORT
      LAYER metal3 ;
      RECT 1.000 84.665 4.000 84.805 ;
    END
  END wd_in[15]
  PIN wd_in[16]
    DIRECTION INPUT ;
    USE SIGNAL ;
    PORT
      LAYER metal3 ;
      RECT 1.000 85.260 3.000 85.330 ;
    END
    PORT
      LAYER metal3 ;
      RECT 1.000 85.225 4.000 85.365 ;
    END
  END wd_in[16]
  PIN wd_in[17]
    DIRECTION INPUT ;
    USE SIGNAL ;
    PORT
      LAYER metal3 ;
      RECT 1.000 85.820 3.000 85.890 ;
    END
    PORT
      LAYER metal3 ;
      RECT 1.000 85.785 4.000 85.925 ;
    END
  END wd_in[17]
  PIN wd_in[18]
    DIRECTION INPUT ;
    USE SIGNAL ;
    PORT
      LAYER metal3 ;
      RECT 1.000 86.380 3.000 86.450 ;
    END
    PORT
      LAYER metal3 ;
      RECT 1.000 86.345 4.000 86.485 ;
    END
  END wd_in[18]
  PIN wd_in[19]
    DIRECTION INPUT ;
    USE SIGNAL ;
    PORT
      LAYER metal3 ;
      RECT 1.000 86.940 3.000 87.010 ;
    END
    PORT
      LAYER metal3 ;
      RECT 1.000 86.905 4.000 87.045 ;
    END
  END wd_in[19]
  PIN wd_in[20]
    DIRECTION INPUT ;
    USE SIGNAL ;
    PORT
      LAYER metal3 ;
      RECT 1.000 87.500 3.000 87.570 ;
    END
    PORT
      LAYER metal3 ;
      RECT 1.000 87.465 4.000 87.605 ;
    END
  END wd_in[20]
  PIN wd_in[21]
    DIRECTION INPUT ;
    USE SIGNAL ;
    PORT
      LAYER metal3 ;
      RECT 1.000 88.060 3.000 88.130 ;
    END
    PORT
      LAYER metal3 ;
      RECT 1.000 88.025 4.000 88.165 ;
    END
  END wd_in[21]
  PIN wd_in[22]
    DIRECTION INPUT ;
    USE SIGNAL ;
    PORT
      LAYER metal3 ;
      RECT 1.000 88.620 3.000 88.690 ;
    END
    PORT
      LAYER metal3 ;
      RECT 1.000 88.585 4.000 88.725 ;
    END
  END wd_in[22]
  PIN wd_in[23]
    DIRECTION INPUT ;
    USE SIGNAL ;
    PORT
      LAYER metal3 ;
      RECT 1.000 89.180 3.000 89.250 ;
    END
    PORT
      LAYER metal3 ;
      RECT 1.000 89.145 4.000 89.285 ;
    END
  END wd_in[23]
  PIN wd_in[24]
    DIRECTION INPUT ;
    USE SIGNAL ;
    PORT
      LAYER metal3 ;
      RECT 1.000 89.740 3.000 89.810 ;
    END
    PORT
      LAYER metal3 ;
      RECT 1.000 89.705 4.000 89.845 ;
    END
  END wd_in[24]
  PIN wd_in[25]
    DIRECTION INPUT ;
    USE SIGNAL ;
    PORT
      LAYER metal3 ;
      RECT 1.000 90.300 3.000 90.370 ;
    END
    PORT
      LAYER metal3 ;
      RECT 1.000 90.265 4.000 90.405 ;
    END
  END wd_in[25]
  PIN wd_in[26]
    DIRECTION INPUT ;
    USE SIGNAL ;
    PORT
      LAYER metal3 ;
      RECT 1.000 90.860 3.000 90.930 ;
    END
    PORT
      LAYER metal3 ;
      RECT 1.000 90.825 4.000 90.965 ;
    END
  END wd_in[26]
  PIN wd_in[27]
    DIRECTION INPUT ;
    USE SIGNAL ;
    PORT
      LAYER metal3 ;
      RECT 1.000 91.420 3.000 91.490 ;
    END
    PORT
      LAYER metal3 ;
      RECT 1.000 91.385 4.000 91.525 ;
    END
  END wd_in[27]
  PIN wd_in[28]
    DIRECTION INPUT ;
    USE SIGNAL ;
    PORT
      LAYER metal3 ;
      RECT 1.000 91.980 3.000 92.050 ;
    END
    PORT
      LAYER metal3 ;
      RECT 1.000 91.945 4.000 92.085 ;
    END
  END wd_in[28]
  PIN wd_in[29]
    DIRECTION INPUT ;
    USE SIGNAL ;
    PORT
      LAYER metal3 ;
      RECT 1.000 92.540 3.000 92.610 ;
    END
    PORT
      LAYER metal3 ;
      RECT 1.000 92.505 4.000 92.645 ;
    END
  END wd_in[29]
  PIN wd_in[30]
    DIRECTION INPUT ;
    USE SIGNAL ;
    PORT
      LAYER metal3 ;
      RECT 1.000 93.100 3.000 93.170 ;
    END
    PORT
      LAYER metal3 ;
      RECT 1.000 93.065 4.000 93.205 ;
    END
  END wd_in[30]
  PIN wd_in[31]
    DIRECTION INPUT ;
    USE SIGNAL ;
    PORT
      LAYER metal3 ;
      RECT 1.000 93.660 3.000 93.730 ;
    END
    PORT
      LAYER metal3 ;
      RECT 1.000 93.625 4.000 93.765 ;
    END
  END wd_in[31]
  PIN wd_in[32]
    DIRECTION INPUT ;
    USE SIGNAL ;
    PORT
      LAYER metal3 ;
      RECT 1.000 94.220 3.000 94.290 ;
    END
    PORT
      LAYER metal3 ;
      RECT 1.000 94.185 4.000 94.325 ;
    END
  END wd_in[32]
  PIN wd_in[33]
    DIRECTION INPUT ;
    USE SIGNAL ;
    PORT
      LAYER metal3 ;
      RECT 1.000 94.780 3.000 94.850 ;
    END
    PORT
      LAYER metal3 ;
      RECT 1.000 94.745 4.000 94.885 ;
    END
  END wd_in[33]
  PIN wd_in[34]
    DIRECTION INPUT ;
    USE SIGNAL ;
    PORT
      LAYER metal3 ;
      RECT 1.000 95.340 3.000 95.410 ;
    END
    PORT
      LAYER metal3 ;
      RECT 1.000 95.305 4.000 95.445 ;
    END
  END wd_in[34]
  PIN wd_in[35]
    DIRECTION INPUT ;
    USE SIGNAL ;
    PORT
      LAYER metal3 ;
      RECT 1.000 95.900 3.000 95.970 ;
    END
    PORT
      LAYER metal3 ;
      RECT 1.000 95.865 4.000 96.005 ;
    END
  END wd_in[35]
  PIN wd_in[36]
    DIRECTION INPUT ;
    USE SIGNAL ;
    PORT
      LAYER metal3 ;
      RECT 1.000 96.460 3.000 96.530 ;
    END
    PORT
      LAYER metal3 ;
      RECT 1.000 96.425 4.000 96.565 ;
    END
  END wd_in[36]
  PIN wd_in[37]
    DIRECTION INPUT ;
    USE SIGNAL ;
    PORT
      LAYER metal3 ;
      RECT 1.000 97.020 3.000 97.090 ;
    END
    PORT
      LAYER metal3 ;
      RECT 1.000 96.985 4.000 97.125 ;
    END
  END wd_in[37]
  PIN wd_in[38]
    DIRECTION INPUT ;
    USE SIGNAL ;
    PORT
      LAYER metal3 ;
      RECT 1.000 97.580 3.000 97.650 ;
    END
    PORT
      LAYER metal3 ;
      RECT 1.000 97.545 4.000 97.685 ;
    END
  END wd_in[38]
  PIN wd_in[39]
    DIRECTION INPUT ;
    USE SIGNAL ;
    PORT
      LAYER metal3 ;
      RECT 1.000 98.140 3.000 98.210 ;
    END
    PORT
      LAYER metal3 ;
      RECT 1.000 98.105 4.000 98.245 ;
    END
  END wd_in[39]
  PIN wd_in[40]
    DIRECTION INPUT ;
    USE SIGNAL ;
    PORT
      LAYER metal3 ;
      RECT 1.000 98.700 3.000 98.770 ;
    END
    PORT
      LAYER metal3 ;
      RECT 1.000 98.665 4.000 98.805 ;
    END
  END wd_in[40]
  PIN wd_in[41]
    DIRECTION INPUT ;
    USE SIGNAL ;
    PORT
      LAYER metal3 ;
      RECT 1.000 99.260 3.000 99.330 ;
    END
    PORT
      LAYER metal3 ;
      RECT 1.000 99.225 4.000 99.365 ;
    END
  END wd_in[41]
  PIN wd_in[42]
    DIRECTION INPUT ;
    USE SIGNAL ;
    PORT
      LAYER metal3 ;
      RECT 1.000 99.820 3.000 99.890 ;
    END
    PORT
      LAYER metal3 ;
      RECT 1.000 99.785 4.000 99.925 ;
    END
  END wd_in[42]
  PIN wd_in[43]
    DIRECTION INPUT ;
    USE SIGNAL ;
    PORT
      LAYER metal3 ;
      RECT 1.000 100.380 3.000 100.450 ;
    END
    PORT
      LAYER metal3 ;
      RECT 1.000 100.345 4.000 100.485 ;
    END
  END wd_in[43]
  PIN wd_in[44]
    DIRECTION INPUT ;
    USE SIGNAL ;
    PORT
      LAYER metal3 ;
      RECT 1.000 100.940 3.000 101.010 ;
    END
    PORT
      LAYER metal3 ;
      RECT 1.000 100.905 4.000 101.045 ;
    END
  END wd_in[44]
  PIN wd_in[45]
    DIRECTION INPUT ;
    USE SIGNAL ;
    PORT
      LAYER metal3 ;
      RECT 1.000 101.500 3.000 101.570 ;
    END
    PORT
      LAYER metal3 ;
      RECT 1.000 101.465 4.000 101.605 ;
    END
  END wd_in[45]
  PIN wd_in[46]
    DIRECTION INPUT ;
    USE SIGNAL ;
    PORT
      LAYER metal3 ;
      RECT 1.000 102.060 3.000 102.130 ;
    END
    PORT
      LAYER metal3 ;
      RECT 1.000 102.025 4.000 102.165 ;
    END
  END wd_in[46]
  PIN wd_in[47]
    DIRECTION INPUT ;
    USE SIGNAL ;
    PORT
      LAYER metal3 ;
      RECT 1.000 102.620 3.000 102.690 ;
    END
    PORT
      LAYER metal3 ;
      RECT 1.000 102.585 4.000 102.725 ;
    END
  END wd_in[47]
  PIN wd_in[48]
    DIRECTION INPUT ;
    USE SIGNAL ;
    PORT
      LAYER metal3 ;
      RECT 1.000 103.180 3.000 103.250 ;
    END
    PORT
      LAYER metal3 ;
      RECT 1.000 103.145 4.000 103.285 ;
    END
  END wd_in[48]
  PIN wd_in[49]
    DIRECTION INPUT ;
    USE SIGNAL ;
    PORT
      LAYER metal3 ;
      RECT 1.000 103.740 3.000 103.810 ;
    END
    PORT
      LAYER metal3 ;
      RECT 1.000 103.705 4.000 103.845 ;
    END
  END wd_in[49]
  PIN wd_in[50]
    DIRECTION INPUT ;
    USE SIGNAL ;
    PORT
      LAYER metal3 ;
      RECT 1.000 104.300 3.000 104.370 ;
    END
    PORT
      LAYER metal3 ;
      RECT 1.000 104.265 4.000 104.405 ;
    END
  END wd_in[50]
  PIN wd_in[51]
    DIRECTION INPUT ;
    USE SIGNAL ;
    PORT
      LAYER metal3 ;
      RECT 1.000 104.860 3.000 104.930 ;
    END
    PORT
      LAYER metal3 ;
      RECT 1.000 104.825 4.000 104.965 ;
    END
  END wd_in[51]
  PIN wd_in[52]
    DIRECTION INPUT ;
    USE SIGNAL ;
    PORT
      LAYER metal3 ;
      RECT 1.000 105.420 3.000 105.490 ;
    END
    PORT
      LAYER metal3 ;
      RECT 1.000 105.385 4.000 105.525 ;
    END
  END wd_in[52]
  PIN wd_in[53]
    DIRECTION INPUT ;
    USE SIGNAL ;
    PORT
      LAYER metal3 ;
      RECT 1.000 105.980 3.000 106.050 ;
    END
    PORT
      LAYER metal3 ;
      RECT 1.000 105.945 4.000 106.085 ;
    END
  END wd_in[53]
  PIN wd_in[54]
    DIRECTION INPUT ;
    USE SIGNAL ;
    PORT
      LAYER metal3 ;
      RECT 1.000 106.540 3.000 106.610 ;
    END
    PORT
      LAYER metal3 ;
      RECT 1.000 106.505 4.000 106.645 ;
    END
  END wd_in[54]
  PIN wd_in[55]
    DIRECTION INPUT ;
    USE SIGNAL ;
    PORT
      LAYER metal3 ;
      RECT 1.000 107.100 3.000 107.170 ;
    END
    PORT
      LAYER metal3 ;
      RECT 1.000 107.065 4.000 107.205 ;
    END
  END wd_in[55]
  PIN wd_in[56]
    DIRECTION INPUT ;
    USE SIGNAL ;
    PORT
      LAYER metal3 ;
      RECT 1.000 107.660 3.000 107.730 ;
    END
    PORT
      LAYER metal3 ;
      RECT 1.000 107.625 4.000 107.765 ;
    END
  END wd_in[56]
  PIN wd_in[57]
    DIRECTION INPUT ;
    USE SIGNAL ;
    PORT
      LAYER metal3 ;
      RECT 1.000 108.220 3.000 108.290 ;
    END
    PORT
      LAYER metal3 ;
      RECT 1.000 108.185 4.000 108.325 ;
    END
  END wd_in[57]
  PIN wd_in[58]
    DIRECTION INPUT ;
    USE SIGNAL ;
    PORT
      LAYER metal3 ;
      RECT 1.000 108.780 3.000 108.850 ;
    END
    PORT
      LAYER metal3 ;
      RECT 1.000 108.745 4.000 108.885 ;
    END
  END wd_in[58]
  PIN wd_in[59]
    DIRECTION INPUT ;
    USE SIGNAL ;
    PORT
      LAYER metal3 ;
      RECT 1.000 109.340 3.000 109.410 ;
    END
    PORT
      LAYER metal3 ;
      RECT 1.000 109.305 4.000 109.445 ;
    END
  END wd_in[59]
  PIN wd_in[60]
    DIRECTION INPUT ;
    USE SIGNAL ;
    PORT
      LAYER metal3 ;
      RECT 1.000 109.900 3.000 109.970 ;
    END
    PORT
      LAYER metal3 ;
      RECT 1.000 109.865 4.000 110.005 ;
    END
  END wd_in[60]
  PIN wd_in[61]
    DIRECTION INPUT ;
    USE SIGNAL ;
    PORT
      LAYER metal3 ;
      RECT 1.000 110.460 3.000 110.530 ;
    END
    PORT
      LAYER metal3 ;
      RECT 1.000 110.425 4.000 110.565 ;
    END
  END wd_in[61]
  PIN wd_in[62]
    DIRECTION INPUT ;
    USE SIGNAL ;
    PORT
      LAYER metal3 ;
      RECT 1.000 111.020 3.000 111.090 ;
    END
    PORT
      LAYER metal3 ;
      RECT 1.000 110.985 4.000 111.125 ;
    END
  END wd_in[62]
  PIN wd_in[63]
    DIRECTION INPUT ;
    USE SIGNAL ;
    PORT
      LAYER metal3 ;
      RECT 1.000 111.580 3.000 111.650 ;
    END
    PORT
      LAYER metal3 ;
      RECT 1.000 111.545 4.000 111.685 ;
    END
  END wd_in[63]
  PIN wd_in[64]
    DIRECTION INPUT ;
    USE SIGNAL ;
    PORT
      LAYER metal3 ;
      RECT 1.000 112.140 3.000 112.210 ;
    END
    PORT
      LAYER metal3 ;
      RECT 1.000 112.105 4.000 112.245 ;
    END
  END wd_in[64]
  PIN wd_in[65]
    DIRECTION INPUT ;
    USE SIGNAL ;
    PORT
      LAYER metal3 ;
      RECT 1.000 112.700 3.000 112.770 ;
    END
    PORT
      LAYER metal3 ;
      RECT 1.000 112.665 4.000 112.805 ;
    END
  END wd_in[65]
  PIN wd_in[66]
    DIRECTION INPUT ;
    USE SIGNAL ;
    PORT
      LAYER metal3 ;
      RECT 1.000 113.260 3.000 113.330 ;
    END
    PORT
      LAYER metal3 ;
      RECT 1.000 113.225 4.000 113.365 ;
    END
  END wd_in[66]
  PIN wd_in[67]
    DIRECTION INPUT ;
    USE SIGNAL ;
    PORT
      LAYER metal3 ;
      RECT 1.000 113.820 3.000 113.890 ;
    END
    PORT
      LAYER metal3 ;
      RECT 1.000 113.785 4.000 113.925 ;
    END
  END wd_in[67]
  PIN wd_in[68]
    DIRECTION INPUT ;
    USE SIGNAL ;
    PORT
      LAYER metal3 ;
      RECT 1.000 114.380 3.000 114.450 ;
    END
    PORT
      LAYER metal3 ;
      RECT 1.000 114.345 4.000 114.485 ;
    END
  END wd_in[68]
  PIN wd_in[69]
    DIRECTION INPUT ;
    USE SIGNAL ;
    PORT
      LAYER metal3 ;
      RECT 1.000 114.940 3.000 115.010 ;
    END
    PORT
      LAYER metal3 ;
      RECT 1.000 114.905 4.000 115.045 ;
    END
  END wd_in[69]
  PIN wd_in[70]
    DIRECTION INPUT ;
    USE SIGNAL ;
    PORT
      LAYER metal3 ;
      RECT 1.000 115.500 3.000 115.570 ;
    END
    PORT
      LAYER metal3 ;
      RECT 1.000 115.465 4.000 115.605 ;
    END
  END wd_in[70]
  PIN wd_in[71]
    DIRECTION INPUT ;
    USE SIGNAL ;
    PORT
      LAYER metal3 ;
      RECT 1.000 116.060 3.000 116.130 ;
    END
    PORT
      LAYER metal3 ;
      RECT 1.000 116.025 4.000 116.165 ;
    END
  END wd_in[71]
  PIN wd_in[72]
    DIRECTION INPUT ;
    USE SIGNAL ;
    PORT
      LAYER metal3 ;
      RECT 1.000 116.620 3.000 116.690 ;
    END
    PORT
      LAYER metal3 ;
      RECT 1.000 116.585 4.000 116.725 ;
    END
  END wd_in[72]
  PIN wd_in[73]
    DIRECTION INPUT ;
    USE SIGNAL ;
    PORT
      LAYER metal3 ;
      RECT 1.000 117.180 3.000 117.250 ;
    END
    PORT
      LAYER metal3 ;
      RECT 1.000 117.145 4.000 117.285 ;
    END
  END wd_in[73]
  PIN wd_in[74]
    DIRECTION INPUT ;
    USE SIGNAL ;
    PORT
      LAYER metal3 ;
      RECT 1.000 117.740 3.000 117.810 ;
    END
    PORT
      LAYER metal3 ;
      RECT 1.000 117.705 4.000 117.845 ;
    END
  END wd_in[74]
  PIN wd_in[75]
    DIRECTION INPUT ;
    USE SIGNAL ;
    PORT
      LAYER metal3 ;
      RECT 1.000 118.300 3.000 118.370 ;
    END
    PORT
      LAYER metal3 ;
      RECT 1.000 118.265 4.000 118.405 ;
    END
  END wd_in[75]
  PIN wd_in[76]
    DIRECTION INPUT ;
    USE SIGNAL ;
    PORT
      LAYER metal3 ;
      RECT 1.000 118.860 3.000 118.930 ;
    END
    PORT
      LAYER metal3 ;
      RECT 1.000 118.825 4.000 118.965 ;
    END
  END wd_in[76]
  PIN wd_in[77]
    DIRECTION INPUT ;
    USE SIGNAL ;
    PORT
      LAYER metal3 ;
      RECT 1.000 119.420 3.000 119.490 ;
    END
    PORT
      LAYER metal3 ;
      RECT 1.000 119.385 4.000 119.525 ;
    END
  END wd_in[77]
  PIN wd_in[78]
    DIRECTION INPUT ;
    USE SIGNAL ;
    PORT
      LAYER metal3 ;
      RECT 1.000 119.980 3.000 120.050 ;
    END
    PORT
      LAYER metal3 ;
      RECT 1.000 119.945 4.000 120.085 ;
    END
  END wd_in[78]
  PIN wd_in[79]
    DIRECTION INPUT ;
    USE SIGNAL ;
    PORT
      LAYER metal3 ;
      RECT 1.000 120.540 3.000 120.610 ;
    END
    PORT
      LAYER metal3 ;
      RECT 1.000 120.505 4.000 120.645 ;
    END
  END wd_in[79]
  PIN wd_in[80]
    DIRECTION INPUT ;
    USE SIGNAL ;
    PORT
      LAYER metal3 ;
      RECT 1.000 121.100 3.000 121.170 ;
    END
    PORT
      LAYER metal3 ;
      RECT 1.000 121.065 4.000 121.205 ;
    END
  END wd_in[80]
  PIN wd_in[81]
    DIRECTION INPUT ;
    USE SIGNAL ;
    PORT
      LAYER metal3 ;
      RECT 1.000 121.660 3.000 121.730 ;
    END
    PORT
      LAYER metal3 ;
      RECT 1.000 121.625 4.000 121.765 ;
    END
  END wd_in[81]
  PIN wd_in[82]
    DIRECTION INPUT ;
    USE SIGNAL ;
    PORT
      LAYER metal3 ;
      RECT 1.000 122.220 3.000 122.290 ;
    END
    PORT
      LAYER metal3 ;
      RECT 1.000 122.185 4.000 122.325 ;
    END
  END wd_in[82]
  PIN wd_in[83]
    DIRECTION INPUT ;
    USE SIGNAL ;
    PORT
      LAYER metal3 ;
      RECT 1.000 122.780 3.000 122.850 ;
    END
    PORT
      LAYER metal3 ;
      RECT 1.000 122.745 4.000 122.885 ;
    END
  END wd_in[83]
  PIN wd_in[84]
    DIRECTION INPUT ;
    USE SIGNAL ;
    PORT
      LAYER metal3 ;
      RECT 1.000 123.340 3.000 123.410 ;
    END
    PORT
      LAYER metal3 ;
      RECT 1.000 123.305 4.000 123.445 ;
    END
  END wd_in[84]
  PIN wd_in[85]
    DIRECTION INPUT ;
    USE SIGNAL ;
    PORT
      LAYER metal3 ;
      RECT 1.000 123.900 3.000 123.970 ;
    END
    PORT
      LAYER metal3 ;
      RECT 1.000 123.865 4.000 124.005 ;
    END
  END wd_in[85]
  PIN wd_in[86]
    DIRECTION INPUT ;
    USE SIGNAL ;
    PORT
      LAYER metal3 ;
      RECT 1.000 124.460 3.000 124.530 ;
    END
    PORT
      LAYER metal3 ;
      RECT 1.000 124.425 4.000 124.565 ;
    END
  END wd_in[86]
  PIN wd_in[87]
    DIRECTION INPUT ;
    USE SIGNAL ;
    PORT
      LAYER metal3 ;
      RECT 1.000 125.020 3.000 125.090 ;
    END
    PORT
      LAYER metal3 ;
      RECT 1.000 124.985 4.000 125.125 ;
    END
  END wd_in[87]
  PIN wd_in[88]
    DIRECTION INPUT ;
    USE SIGNAL ;
    PORT
      LAYER metal3 ;
      RECT 1.000 125.580 3.000 125.650 ;
    END
    PORT
      LAYER metal3 ;
      RECT 1.000 125.545 4.000 125.685 ;
    END
  END wd_in[88]
  PIN wd_in[89]
    DIRECTION INPUT ;
    USE SIGNAL ;
    PORT
      LAYER metal3 ;
      RECT 1.000 126.140 3.000 126.210 ;
    END
    PORT
      LAYER metal3 ;
      RECT 1.000 126.105 4.000 126.245 ;
    END
  END wd_in[89]
  PIN wd_in[90]
    DIRECTION INPUT ;
    USE SIGNAL ;
    PORT
      LAYER metal3 ;
      RECT 1.000 126.700 3.000 126.770 ;
    END
    PORT
      LAYER metal3 ;
      RECT 1.000 126.665 4.000 126.805 ;
    END
  END wd_in[90]
  PIN wd_in[91]
    DIRECTION INPUT ;
    USE SIGNAL ;
    PORT
      LAYER metal3 ;
      RECT 1.000 127.260 3.000 127.330 ;
    END
    PORT
      LAYER metal3 ;
      RECT 1.000 127.225 4.000 127.365 ;
    END
  END wd_in[91]
  PIN wd_in[92]
    DIRECTION INPUT ;
    USE SIGNAL ;
    PORT
      LAYER metal3 ;
      RECT 1.000 127.820 3.000 127.890 ;
    END
    PORT
      LAYER metal3 ;
      RECT 1.000 127.785 4.000 127.925 ;
    END
  END wd_in[92]
  PIN wd_in[93]
    DIRECTION INPUT ;
    USE SIGNAL ;
    PORT
      LAYER metal3 ;
      RECT 1.000 128.380 3.000 128.450 ;
    END
    PORT
      LAYER metal3 ;
      RECT 1.000 128.345 4.000 128.485 ;
    END
  END wd_in[93]
  PIN wd_in[94]
    DIRECTION INPUT ;
    USE SIGNAL ;
    PORT
      LAYER metal3 ;
      RECT 1.000 128.940 3.000 129.010 ;
    END
    PORT
      LAYER metal3 ;
      RECT 1.000 128.905 4.000 129.045 ;
    END
  END wd_in[94]
  PIN wd_in[95]
    DIRECTION INPUT ;
    USE SIGNAL ;
    PORT
      LAYER metal3 ;
      RECT 1.000 129.500 3.000 129.570 ;
    END
    PORT
      LAYER metal3 ;
      RECT 1.000 129.465 4.000 129.605 ;
    END
  END wd_in[95]
  PIN wd_in[96]
    DIRECTION INPUT ;
    USE SIGNAL ;
    PORT
      LAYER metal3 ;
      RECT 1.000 130.060 3.000 130.130 ;
    END
    PORT
      LAYER metal3 ;
      RECT 1.000 130.025 4.000 130.165 ;
    END
  END wd_in[96]
  PIN wd_in[97]
    DIRECTION INPUT ;
    USE SIGNAL ;
    PORT
      LAYER metal3 ;
      RECT 1.000 130.620 3.000 130.690 ;
    END
    PORT
      LAYER metal3 ;
      RECT 1.000 130.585 4.000 130.725 ;
    END
  END wd_in[97]
  PIN wd_in[98]
    DIRECTION INPUT ;
    USE SIGNAL ;
    PORT
      LAYER metal3 ;
      RECT 1.000 131.180 3.000 131.250 ;
    END
    PORT
      LAYER metal3 ;
      RECT 1.000 131.145 4.000 131.285 ;
    END
  END wd_in[98]
  PIN wd_in[99]
    DIRECTION INPUT ;
    USE SIGNAL ;
    PORT
      LAYER metal3 ;
      RECT 1.000 131.740 3.000 131.810 ;
    END
    PORT
      LAYER metal3 ;
      RECT 1.000 131.705 4.000 131.845 ;
    END
  END wd_in[99]
  PIN wd_in[100]
    DIRECTION INPUT ;
    USE SIGNAL ;
    PORT
      LAYER metal3 ;
      RECT 1.000 132.300 3.000 132.370 ;
    END
    PORT
      LAYER metal3 ;
      RECT 1.000 132.265 4.000 132.405 ;
    END
  END wd_in[100]
  PIN wd_in[101]
    DIRECTION INPUT ;
    USE SIGNAL ;
    PORT
      LAYER metal3 ;
      RECT 1.000 132.860 3.000 132.930 ;
    END
    PORT
      LAYER metal3 ;
      RECT 1.000 132.825 4.000 132.965 ;
    END
  END wd_in[101]
  PIN wd_in[102]
    DIRECTION INPUT ;
    USE SIGNAL ;
    PORT
      LAYER metal3 ;
      RECT 1.000 133.420 3.000 133.490 ;
    END
    PORT
      LAYER metal3 ;
      RECT 1.000 133.385 4.000 133.525 ;
    END
  END wd_in[102]
  PIN wd_in[103]
    DIRECTION INPUT ;
    USE SIGNAL ;
    PORT
      LAYER metal3 ;
      RECT 1.000 133.980 3.000 134.050 ;
    END
    PORT
      LAYER metal3 ;
      RECT 1.000 133.945 4.000 134.085 ;
    END
  END wd_in[103]
  PIN wd_in[104]
    DIRECTION INPUT ;
    USE SIGNAL ;
    PORT
      LAYER metal3 ;
      RECT 1.000 134.540 3.000 134.610 ;
    END
    PORT
      LAYER metal3 ;
      RECT 1.000 134.505 4.000 134.645 ;
    END
  END wd_in[104]
  PIN wd_in[105]
    DIRECTION INPUT ;
    USE SIGNAL ;
    PORT
      LAYER metal3 ;
      RECT 1.000 135.100 3.000 135.170 ;
    END
    PORT
      LAYER metal3 ;
      RECT 1.000 135.065 4.000 135.205 ;
    END
  END wd_in[105]
  PIN wd_in[106]
    DIRECTION INPUT ;
    USE SIGNAL ;
    PORT
      LAYER metal3 ;
      RECT 1.000 135.660 3.000 135.730 ;
    END
    PORT
      LAYER metal3 ;
      RECT 1.000 135.625 4.000 135.765 ;
    END
  END wd_in[106]
  PIN wd_in[107]
    DIRECTION INPUT ;
    USE SIGNAL ;
    PORT
      LAYER metal3 ;
      RECT 1.000 136.220 3.000 136.290 ;
    END
    PORT
      LAYER metal3 ;
      RECT 1.000 136.185 4.000 136.325 ;
    END
  END wd_in[107]
  PIN wd_in[108]
    DIRECTION INPUT ;
    USE SIGNAL ;
    PORT
      LAYER metal3 ;
      RECT 1.000 136.780 3.000 136.850 ;
    END
    PORT
      LAYER metal3 ;
      RECT 1.000 136.745 4.000 136.885 ;
    END
  END wd_in[108]
  PIN wd_in[109]
    DIRECTION INPUT ;
    USE SIGNAL ;
    PORT
      LAYER metal3 ;
      RECT 1.000 137.340 3.000 137.410 ;
    END
    PORT
      LAYER metal3 ;
      RECT 1.000 137.305 4.000 137.445 ;
    END
  END wd_in[109]
  PIN wd_in[110]
    DIRECTION INPUT ;
    USE SIGNAL ;
    PORT
      LAYER metal3 ;
      RECT 1.000 137.900 3.000 137.970 ;
    END
    PORT
      LAYER metal3 ;
      RECT 1.000 137.865 4.000 138.005 ;
    END
  END wd_in[110]
  PIN wd_in[111]
    DIRECTION INPUT ;
    USE SIGNAL ;
    PORT
      LAYER metal3 ;
      RECT 1.000 138.460 3.000 138.530 ;
    END
    PORT
      LAYER metal3 ;
      RECT 1.000 138.425 4.000 138.565 ;
    END
  END wd_in[111]
  PIN wd_in[112]
    DIRECTION INPUT ;
    USE SIGNAL ;
    PORT
      LAYER metal3 ;
      RECT 1.000 139.020 3.000 139.090 ;
    END
    PORT
      LAYER metal3 ;
      RECT 1.000 138.985 4.000 139.125 ;
    END
  END wd_in[112]
  PIN wd_in[113]
    DIRECTION INPUT ;
    USE SIGNAL ;
    PORT
      LAYER metal3 ;
      RECT 1.000 139.580 3.000 139.650 ;
    END
    PORT
      LAYER metal3 ;
      RECT 1.000 139.545 4.000 139.685 ;
    END
  END wd_in[113]
  PIN wd_in[114]
    DIRECTION INPUT ;
    USE SIGNAL ;
    PORT
      LAYER metal3 ;
      RECT 1.000 140.140 3.000 140.210 ;
    END
    PORT
      LAYER metal3 ;
      RECT 1.000 140.105 4.000 140.245 ;
    END
  END wd_in[114]
  PIN wd_in[115]
    DIRECTION INPUT ;
    USE SIGNAL ;
    PORT
      LAYER metal3 ;
      RECT 1.000 140.700 3.000 140.770 ;
    END
    PORT
      LAYER metal3 ;
      RECT 1.000 140.665 4.000 140.805 ;
    END
  END wd_in[115]
  PIN wd_in[116]
    DIRECTION INPUT ;
    USE SIGNAL ;
    PORT
      LAYER metal3 ;
      RECT 1.000 141.260 3.000 141.330 ;
    END
    PORT
      LAYER metal3 ;
      RECT 1.000 141.225 4.000 141.365 ;
    END
  END wd_in[116]
  PIN wd_in[117]
    DIRECTION INPUT ;
    USE SIGNAL ;
    PORT
      LAYER metal3 ;
      RECT 1.000 141.820 3.000 141.890 ;
    END
    PORT
      LAYER metal3 ;
      RECT 1.000 141.785 4.000 141.925 ;
    END
  END wd_in[117]
  PIN wd_in[118]
    DIRECTION INPUT ;
    USE SIGNAL ;
    PORT
      LAYER metal3 ;
      RECT 1.000 142.380 3.000 142.450 ;
    END
    PORT
      LAYER metal3 ;
      RECT 1.000 142.345 4.000 142.485 ;
    END
  END wd_in[118]
  PIN wd_in[119]
    DIRECTION INPUT ;
    USE SIGNAL ;
    PORT
      LAYER metal3 ;
      RECT 1.000 142.940 3.000 143.010 ;
    END
    PORT
      LAYER metal3 ;
      RECT 1.000 142.905 4.000 143.045 ;
    END
  END wd_in[119]
  PIN wd_in[120]
    DIRECTION INPUT ;
    USE SIGNAL ;
    PORT
      LAYER metal3 ;
      RECT 1.000 143.500 3.000 143.570 ;
    END
    PORT
      LAYER metal3 ;
      RECT 1.000 143.465 4.000 143.605 ;
    END
  END wd_in[120]
  PIN wd_in[121]
    DIRECTION INPUT ;
    USE SIGNAL ;
    PORT
      LAYER metal3 ;
      RECT 1.000 144.060 3.000 144.130 ;
    END
    PORT
      LAYER metal3 ;
      RECT 1.000 144.025 4.000 144.165 ;
    END
  END wd_in[121]
  PIN wd_in[122]
    DIRECTION INPUT ;
    USE SIGNAL ;
    PORT
      LAYER metal3 ;
      RECT 1.000 144.620 3.000 144.690 ;
    END
    PORT
      LAYER metal3 ;
      RECT 1.000 144.585 4.000 144.725 ;
    END
  END wd_in[122]
  PIN wd_in[123]
    DIRECTION INPUT ;
    USE SIGNAL ;
    PORT
      LAYER metal3 ;
      RECT 1.000 145.180 3.000 145.250 ;
    END
    PORT
      LAYER metal3 ;
      RECT 1.000 145.145 4.000 145.285 ;
    END
  END wd_in[123]
  PIN wd_in[124]
    DIRECTION INPUT ;
    USE SIGNAL ;
    PORT
      LAYER metal3 ;
      RECT 1.000 145.740 3.000 145.810 ;
    END
    PORT
      LAYER metal3 ;
      RECT 1.000 145.705 4.000 145.845 ;
    END
  END wd_in[124]
  PIN wd_in[125]
    DIRECTION INPUT ;
    USE SIGNAL ;
    PORT
      LAYER metal3 ;
      RECT 1.000 146.300 3.000 146.370 ;
    END
    PORT
      LAYER metal3 ;
      RECT 1.000 146.265 4.000 146.405 ;
    END
  END wd_in[125]
  PIN wd_in[126]
    DIRECTION INPUT ;
    USE SIGNAL ;
    PORT
      LAYER metal3 ;
      RECT 1.000 146.860 3.000 146.930 ;
    END
    PORT
      LAYER metal3 ;
      RECT 1.000 146.825 4.000 146.965 ;
    END
  END wd_in[126]
  PIN wd_in[127]
    DIRECTION INPUT ;
    USE SIGNAL ;
    PORT
      LAYER metal3 ;
      RECT 1.000 147.420 3.000 147.490 ;
    END
    PORT
      LAYER metal3 ;
      RECT 1.000 147.385 4.000 147.525 ;
    END
  END wd_in[127]
  PIN addr_in[0]
    DIRECTION INPUT ;
    USE SIGNAL ;
    PORT
      LAYER metal3 ;
      RECT 1.000 152.460 3.000 152.530 ;
    END
    PORT
      LAYER metal3 ;
      RECT 1.000 152.425 4.000 152.565 ;
    END
  END addr_in[0]
  PIN addr_in[1]
    DIRECTION INPUT ;
    USE SIGNAL ;
    PORT
      LAYER metal3 ;
      RECT 1.000 153.020 3.000 153.090 ;
    END
    PORT
      LAYER metal3 ;
      RECT 1.000 152.985 4.000 153.125 ;
    END
  END addr_in[1]
  PIN addr_in[2]
    DIRECTION INPUT ;
    USE SIGNAL ;
    PORT
      LAYER metal3 ;
      RECT 1.000 153.580 3.000 153.650 ;
    END
    PORT
      LAYER metal3 ;
      RECT 1.000 153.545 4.000 153.685 ;
    END
  END addr_in[2]
  PIN addr_in[3]
    DIRECTION INPUT ;
    USE SIGNAL ;
    PORT
      LAYER metal3 ;
      RECT 1.000 154.140 3.000 154.210 ;
    END
    PORT
      LAYER metal3 ;
      RECT 1.000 154.105 4.000 154.245 ;
    END
  END addr_in[3]
  PIN addr_in[4]
    DIRECTION INPUT ;
    USE SIGNAL ;
    PORT
      LAYER metal3 ;
      RECT 1.000 154.700 3.000 154.770 ;
    END
    PORT
      LAYER metal3 ;
      RECT 1.000 154.665 4.000 154.805 ;
    END
  END addr_in[4]
  PIN addr_in[5]
    DIRECTION INPUT ;
    USE SIGNAL ;
    PORT
      LAYER metal3 ;
      RECT 1.000 155.260 3.000 155.330 ;
    END
    PORT
      LAYER metal3 ;
      RECT 1.000 155.225 4.000 155.365 ;
    END
  END addr_in[5]
  PIN we_in
    DIRECTION INPUT ;
    USE SIGNAL ;
    PORT
      LAYER metal3 ;
      RECT 1.000 160.300 3.000 160.370 ;
    END
    PORT
      LAYER metal3 ;
      RECT 1.000 160.265 4.000 160.405 ;
    END
  END we_in
  PIN ce_in
    DIRECTION INPUT ;
    USE SIGNAL ;
    PORT
      LAYER metal3 ;
      RECT 1.000 160.860 3.000 160.930 ;
    END
    PORT
      LAYER metal3 ;
      RECT 1.000 160.825 4.000 160.965 ;
    END
  END ce_in
  PIN clk
    DIRECTION INPUT ;
    USE SIGNAL ;
    PORT
      LAYER metal3 ;
      RECT 1.000 161.420 3.000 161.490 ;
    END
    PORT
      LAYER metal3 ;
      RECT 1.000 161.385 4.000 161.525 ;
    END
  END clk
  PIN VSS
    DIRECTION INOUT ;
    USE GROUND ;
    PORT
      LAYER metal3 ;
      RECT 0.140 0.000 64.400 0.280 ;
      RECT 0.140 2.240 64.400 2.520 ;
      RECT 0.140 4.480 64.400 4.760 ;
      RECT 0.140 6.720 64.400 7.000 ;
      RECT 0.140 8.960 64.400 9.240 ;
      RECT 0.140 11.200 64.400 11.480 ;
      RECT 0.140 13.440 64.400 13.720 ;
      RECT 0.140 15.680 64.400 15.960 ;
      RECT 0.140 17.920 64.400 18.200 ;
      RECT 0.140 20.160 64.400 20.440 ;
      RECT 0.140 22.400 64.400 22.680 ;
      RECT 0.140 24.640 64.400 24.920 ;
      RECT 0.140 26.880 64.400 27.160 ;
      RECT 0.140 29.120 64.400 29.400 ;
      RECT 0.140 31.360 64.400 31.640 ;
      RECT 0.140 33.600 64.400 33.880 ;
      RECT 0.140 35.840 64.400 36.120 ;
      RECT 0.140 38.080 64.400 38.360 ;
      RECT 0.140 40.320 64.400 40.600 ;
      RECT 0.140 42.560 64.400 42.840 ;
      RECT 0.140 44.800 64.400 45.080 ;
      RECT 0.140 47.040 64.400 47.320 ;
      RECT 0.140 49.280 64.400 49.560 ;
      RECT 0.140 51.520 64.400 51.800 ;
      RECT 0.140 53.760 64.400 54.040 ;
      RECT 0.140 56.000 64.400 56.280 ;
      RECT 0.140 58.240 64.400 58.520 ;
      RECT 0.140 60.480 64.400 60.760 ;
      RECT 0.140 62.720 64.400 63.000 ;
      RECT 0.140 64.960 64.400 65.240 ;
      RECT 0.140 67.200 64.400 67.480 ;
      RECT 0.140 69.440 64.400 69.720 ;
      RECT 0.140 71.680 64.400 71.960 ;
      RECT 0.140 73.920 64.400 74.200 ;
      RECT 0.140 76.160 64.400 76.440 ;
      RECT 0.140 78.400 64.400 78.680 ;
      RECT 0.140 80.640 64.400 80.920 ;
      RECT 0.140 82.880 64.400 83.160 ;
      RECT 0.140 85.120 64.400 85.400 ;
      RECT 0.140 87.360 64.400 87.640 ;
      RECT 0.140 89.600 64.400 89.880 ;
      RECT 0.140 91.840 64.400 92.120 ;
      RECT 0.140 94.080 64.400 94.360 ;
      RECT 0.140 96.320 64.400 96.600 ;
      RECT 0.140 98.560 64.400 98.840 ;
      RECT 0.140 100.800 64.400 101.080 ;
      RECT 0.140 103.040 64.400 103.320 ;
      RECT 0.140 105.280 64.400 105.560 ;
      RECT 0.140 107.520 64.400 107.800 ;
      RECT 0.140 109.760 64.400 110.040 ;
      RECT 0.140 112.000 64.400 112.280 ;
      RECT 0.140 114.240 64.400 114.520 ;
      RECT 0.140 116.480 64.400 116.760 ;
      RECT 0.140 118.720 64.400 119.000 ;
      RECT 0.140 120.960 64.400 121.240 ;
      RECT 0.140 123.200 64.400 123.480 ;
      RECT 0.140 125.440 64.400 125.720 ;
      RECT 0.140 127.680 64.400 127.960 ;
      RECT 0.140 129.920 64.400 130.200 ;
      RECT 0.140 132.160 64.400 132.440 ;
      RECT 0.140 134.400 64.400 134.680 ;
      RECT 0.140 136.640 64.400 136.920 ;
      RECT 0.140 138.880 64.400 139.160 ;
      RECT 0.140 141.120 64.400 141.400 ;
      RECT 0.140 143.360 64.400 143.640 ;
      RECT 0.140 145.600 64.400 145.880 ;
      RECT 0.140 147.840 64.400 148.120 ;
      RECT 0.140 150.080 64.400 150.360 ;
      RECT 0.140 152.320 64.400 152.600 ;
      RECT 0.140 154.560 64.400 154.840 ;
      RECT 0.140 156.800 64.400 157.080 ;
      RECT 0.140 159.040 64.400 159.320 ;
      RECT 0.140 161.280 64.400 161.560 ;
    END
  END VSS
  PIN VDD
    DIRECTION INOUT ;
    USE POWER ;
    PORT
      LAYER metal3 ;
      RECT 0.140 1.120 64.400 1.400 ;
      RECT 0.140 3.360 64.400 3.640 ;
      RECT 0.140 5.600 64.400 5.880 ;
      RECT 0.140 7.840 64.400 8.120 ;
      RECT 0.140 10.080 64.400 10.360 ;
      RECT 0.140 12.320 64.400 12.600 ;
      RECT 0.140 14.560 64.400 14.840 ;
      RECT 0.140 16.800 64.400 17.080 ;
      RECT 0.140 19.040 64.400 19.320 ;
      RECT 0.140 21.280 64.400 21.560 ;
      RECT 0.140 23.520 64.400 23.800 ;
      RECT 0.140 25.760 64.400 26.040 ;
      RECT 0.140 28.000 64.400 28.280 ;
      RECT 0.140 30.240 64.400 30.520 ;
      RECT 0.140 32.480 64.400 32.760 ;
      RECT 0.140 34.720 64.400 35.000 ;
      RECT 0.140 36.960 64.400 37.240 ;
      RECT 0.140 39.200 64.400 39.480 ;
      RECT 0.140 41.440 64.400 41.720 ;
      RECT 0.140 43.680 64.400 43.960 ;
      RECT 0.140 45.920 64.400 46.200 ;
      RECT 0.140 48.160 64.400 48.440 ;
      RECT 0.140 50.400 64.400 50.680 ;
      RECT 0.140 52.640 64.400 52.920 ;
      RECT 0.140 54.880 64.400 55.160 ;
      RECT 0.140 57.120 64.400 57.400 ;
      RECT 0.140 59.360 64.400 59.640 ;
      RECT 0.140 61.600 64.400 61.880 ;
      RECT 0.140 63.840 64.400 64.120 ;
      RECT 0.140 66.080 64.400 66.360 ;
      RECT 0.140 68.320 64.400 68.600 ;
      RECT 0.140 70.560 64.400 70.840 ;
      RECT 0.140 72.800 64.400 73.080 ;
      RECT 0.140 75.040 64.400 75.320 ;
      RECT 0.140 77.280 64.400 77.560 ;
      RECT 0.140 79.520 64.400 79.800 ;
      RECT 0.140 81.760 64.400 82.040 ;
      RECT 0.140 84.000 64.400 84.280 ;
      RECT 0.140 86.240 64.400 86.520 ;
      RECT 0.140 88.480 64.400 88.760 ;
      RECT 0.140 90.720 64.400 91.000 ;
      RECT 0.140 92.960 64.400 93.240 ;
      RECT 0.140 95.200 64.400 95.480 ;
      RECT 0.140 97.440 64.400 97.720 ;
      RECT 0.140 99.680 64.400 99.960 ;
      RECT 0.140 101.920 64.400 102.200 ;
      RECT 0.140 104.160 64.400 104.440 ;
      RECT 0.140 106.400 64.400 106.680 ;
      RECT 0.140 108.640 64.400 108.920 ;
      RECT 0.140 110.880 64.400 111.160 ;
      RECT 0.140 113.120 64.400 113.400 ;
      RECT 0.140 115.360 64.400 115.640 ;
      RECT 0.140 117.600 64.400 117.880 ;
      RECT 0.140 119.840 64.400 120.120 ;
      RECT 0.140 122.080 64.400 122.360 ;
      RECT 0.140 124.320 64.400 124.600 ;
      RECT 0.140 126.560 64.400 126.840 ;
      RECT 0.140 128.800 64.400 129.080 ;
      RECT 0.140 131.040 64.400 131.320 ;
      RECT 0.140 133.280 64.400 133.560 ;
      RECT 0.140 135.520 64.400 135.800 ;
      RECT 0.140 137.760 64.400 138.040 ;
      RECT 0.140 140.000 64.400 140.280 ;
      RECT 0.140 142.240 64.400 142.520 ;
      RECT 0.140 144.480 64.400 144.760 ;
      RECT 0.140 146.720 64.400 147.000 ;
      RECT 0.140 148.960 64.400 149.240 ;
      RECT 0.140 151.200 64.400 151.480 ;
      RECT 0.140 153.440 64.400 153.720 ;
      RECT 0.140 155.680 64.400 155.960 ;
      RECT 0.140 157.920 64.400 158.200 ;
      RECT 0.140 160.160 64.400 160.440 ;
    END
  END VDD
  OBS
    LAYER metal1 ;
    RECT 0 0 64.540 162.400 ;
    LAYER metal2 ;
    RECT 0 0 64.540 162.400 ;
  END
END fakeram_128x64
END LIBRARY
